VERSION 5.7 ;
  NOWIREEXTENSIONATPIN ON ;
  DIVIDERCHAR "/" ;
  BUSBITCHARS "[]" ;
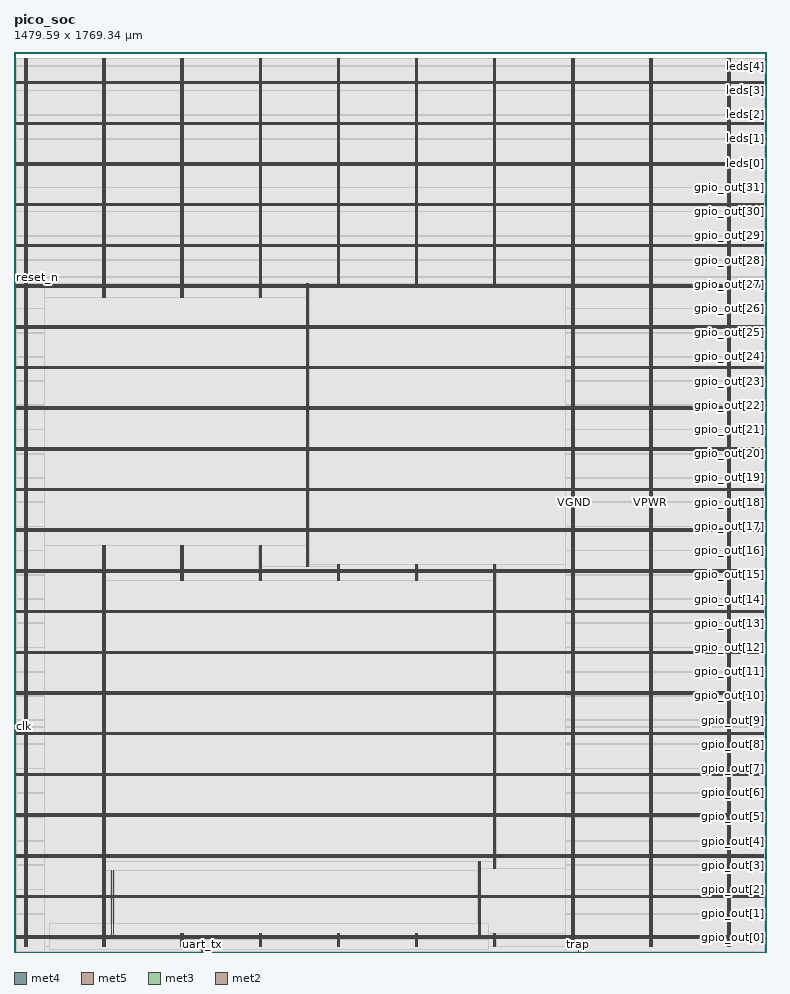
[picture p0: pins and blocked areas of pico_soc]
MACRO pico_soc
  CLASS BLOCK ;
  FOREIGN pico_soc ;
  ORIGIN 0.000 0.000 ;
  SIZE 1479.590 BY 1769.335 ;
  PIN VGND
    DIRECTION INOUT ;
    USE GROUND ;
    PORT
      LAYER met4 ;
        RECT 24.340 10.640 25.940 1757.360 ;
    END
    PORT
      LAYER met4 ;
        RECT 177.940 10.640 179.540 799.645 ;
    END
    PORT
      LAYER met4 ;
        RECT 177.940 1287.055 179.540 1757.360 ;
    END
    PORT
      LAYER met4 ;
        RECT 331.540 10.640 333.140 35.515 ;
    END
    PORT
      LAYER met4 ;
        RECT 331.540 730.325 333.140 799.645 ;
    END
    PORT
      LAYER met4 ;
        RECT 331.540 1287.055 333.140 1757.360 ;
    END
    PORT
      LAYER met4 ;
        RECT 485.140 10.640 486.740 35.515 ;
    END
    PORT
      LAYER met4 ;
        RECT 485.140 730.325 486.740 799.645 ;
    END
    PORT
      LAYER met4 ;
        RECT 485.140 1287.055 486.740 1757.360 ;
    END
    PORT
      LAYER met4 ;
        RECT 638.740 10.640 640.340 35.515 ;
    END
    PORT
      LAYER met4 ;
        RECT 638.740 730.325 640.340 762.080 ;
    END
    PORT
      LAYER met4 ;
        RECT 638.740 1310.030 640.340 1757.360 ;
    END
    PORT
      LAYER met4 ;
        RECT 792.340 10.640 793.940 35.515 ;
    END
    PORT
      LAYER met4 ;
        RECT 792.340 730.325 793.940 762.080 ;
    END
    PORT
      LAYER met4 ;
        RECT 792.340 1310.030 793.940 1757.360 ;
    END
    PORT
      LAYER met4 ;
        RECT 945.940 10.640 947.540 35.995 ;
    END
    PORT
      LAYER met4 ;
        RECT 945.940 163.685 947.540 762.080 ;
    END
    PORT
      LAYER met4 ;
        RECT 945.940 1310.030 947.540 1757.360 ;
    END
    PORT
      LAYER met4 ;
        RECT 1099.540 10.640 1101.140 1757.360 ;
    END
    PORT
      LAYER met4 ;
        RECT 1253.140 10.640 1254.740 1757.360 ;
    END
    PORT
      LAYER met4 ;
        RECT 1406.740 10.640 1408.340 1757.360 ;
    END
    PORT
      LAYER met5 ;
        RECT 5.280 30.030 1474.080 31.630 ;
    END
    PORT
      LAYER met5 ;
        RECT 5.280 110.030 1474.080 111.630 ;
    END
    PORT
      LAYER met5 ;
        RECT 5.280 190.030 1474.080 191.630 ;
    END
    PORT
      LAYER met5 ;
        RECT 5.280 270.030 1474.080 271.630 ;
    END
    PORT
      LAYER met5 ;
        RECT 5.280 350.030 1474.080 351.630 ;
    END
    PORT
      LAYER met5 ;
        RECT 5.280 430.030 1474.080 431.630 ;
    END
    PORT
      LAYER met5 ;
        RECT 5.280 510.030 1474.080 511.630 ;
    END
    PORT
      LAYER met5 ;
        RECT 5.280 590.030 1474.080 591.630 ;
    END
    PORT
      LAYER met5 ;
        RECT 5.280 670.030 1474.080 671.630 ;
    END
    PORT
      LAYER met5 ;
        RECT 5.280 750.030 1474.080 751.630 ;
    END
    PORT
      LAYER met5 ;
        RECT 5.280 830.030 1474.080 831.630 ;
    END
    PORT
      LAYER met5 ;
        RECT 5.280 910.030 1474.080 911.630 ;
    END
    PORT
      LAYER met5 ;
        RECT 5.280 990.030 1474.080 991.630 ;
    END
    PORT
      LAYER met5 ;
        RECT 5.280 1070.030 1474.080 1071.630 ;
    END
    PORT
      LAYER met5 ;
        RECT 5.280 1150.030 1474.080 1151.630 ;
    END
    PORT
      LAYER met5 ;
        RECT 5.280 1230.030 1474.080 1231.630 ;
    END
    PORT
      LAYER met5 ;
        RECT 5.280 1310.030 1474.080 1311.630 ;
    END
    PORT
      LAYER met5 ;
        RECT 5.280 1390.030 1474.080 1391.630 ;
    END
    PORT
      LAYER met5 ;
        RECT 5.280 1470.030 1474.080 1471.630 ;
    END
    PORT
      LAYER met5 ;
        RECT 5.280 1550.030 1474.080 1551.630 ;
    END
    PORT
      LAYER met5 ;
        RECT 5.280 1630.030 1474.080 1631.630 ;
    END
    PORT
      LAYER met5 ;
        RECT 5.280 1710.030 1474.080 1711.630 ;
    END
    PORT
      LAYER met4 ;
        RECT 194.700 26.960 196.300 160.720 ;
    END
    PORT
      LAYER met4 ;
        RECT 578.340 758.640 579.940 1314.000 ;
    END
    PORT
      LAYER met4 ;
        RECT 915.980 26.960 917.580 177.040 ;
    END
  END VGND
  PIN VPWR
    DIRECTION INOUT ;
    USE POWER ;
    PORT
      LAYER met4 ;
        RECT 21.040 10.640 22.640 1757.360 ;
    END
    PORT
      LAYER met4 ;
        RECT 174.640 10.640 176.240 799.645 ;
    END
    PORT
      LAYER met4 ;
        RECT 174.640 1287.055 176.240 1757.360 ;
    END
    PORT
      LAYER met4 ;
        RECT 328.240 10.640 329.840 35.515 ;
    END
    PORT
      LAYER met4 ;
        RECT 328.240 730.325 329.840 799.645 ;
    END
    PORT
      LAYER met4 ;
        RECT 328.240 1287.055 329.840 1757.360 ;
    END
    PORT
      LAYER met4 ;
        RECT 481.840 10.640 483.440 35.515 ;
    END
    PORT
      LAYER met4 ;
        RECT 481.840 730.325 483.440 799.645 ;
    END
    PORT
      LAYER met4 ;
        RECT 481.840 1287.055 483.440 1757.360 ;
    END
    PORT
      LAYER met4 ;
        RECT 635.440 10.640 637.040 35.515 ;
    END
    PORT
      LAYER met4 ;
        RECT 635.440 730.325 637.040 762.080 ;
    END
    PORT
      LAYER met4 ;
        RECT 635.440 1310.295 637.040 1757.360 ;
    END
    PORT
      LAYER met4 ;
        RECT 789.040 10.640 790.640 35.515 ;
    END
    PORT
      LAYER met4 ;
        RECT 789.040 730.325 790.640 761.160 ;
    END
    PORT
      LAYER met4 ;
        RECT 789.040 1310.295 790.640 1757.360 ;
    END
    PORT
      LAYER met4 ;
        RECT 942.640 10.640 944.240 35.995 ;
    END
    PORT
      LAYER met4 ;
        RECT 942.640 163.685 944.240 762.080 ;
    END
    PORT
      LAYER met4 ;
        RECT 942.640 1310.295 944.240 1757.360 ;
    END
    PORT
      LAYER met4 ;
        RECT 1096.240 10.640 1097.840 1757.360 ;
    END
    PORT
      LAYER met4 ;
        RECT 1249.840 10.640 1251.440 1757.360 ;
    END
    PORT
      LAYER met4 ;
        RECT 1403.440 10.640 1405.040 1757.360 ;
    END
    PORT
      LAYER met5 ;
        RECT 5.280 26.730 1474.080 28.330 ;
    END
    PORT
      LAYER met5 ;
        RECT 5.280 106.730 1474.080 108.330 ;
    END
    PORT
      LAYER met5 ;
        RECT 5.280 186.730 1474.080 188.330 ;
    END
    PORT
      LAYER met5 ;
        RECT 5.280 266.730 1474.080 268.330 ;
    END
    PORT
      LAYER met5 ;
        RECT 5.280 346.730 1474.080 348.330 ;
    END
    PORT
      LAYER met5 ;
        RECT 5.280 426.730 1474.080 428.330 ;
    END
    PORT
      LAYER met5 ;
        RECT 5.280 506.730 1474.080 508.330 ;
    END
    PORT
      LAYER met5 ;
        RECT 5.280 586.730 1474.080 588.330 ;
    END
    PORT
      LAYER met5 ;
        RECT 5.280 666.730 1474.080 668.330 ;
    END
    PORT
      LAYER met5 ;
        RECT 5.280 746.730 1474.080 748.330 ;
    END
    PORT
      LAYER met5 ;
        RECT 5.280 826.730 1474.080 828.330 ;
    END
    PORT
      LAYER met5 ;
        RECT 5.280 906.730 1474.080 908.330 ;
    END
    PORT
      LAYER met5 ;
        RECT 5.280 986.730 1474.080 988.330 ;
    END
    PORT
      LAYER met5 ;
        RECT 5.280 1066.730 1474.080 1068.330 ;
    END
    PORT
      LAYER met5 ;
        RECT 5.280 1146.730 1474.080 1148.330 ;
    END
    PORT
      LAYER met5 ;
        RECT 5.280 1226.730 1474.080 1228.330 ;
    END
    PORT
      LAYER met5 ;
        RECT 5.280 1306.730 1474.080 1308.330 ;
    END
    PORT
      LAYER met5 ;
        RECT 5.280 1386.730 1474.080 1388.330 ;
    END
    PORT
      LAYER met5 ;
        RECT 5.280 1466.730 1474.080 1468.330 ;
    END
    PORT
      LAYER met5 ;
        RECT 5.280 1546.730 1474.080 1548.330 ;
    END
    PORT
      LAYER met5 ;
        RECT 5.280 1626.730 1474.080 1628.330 ;
    END
    PORT
      LAYER met5 ;
        RECT 5.280 1706.730 1474.080 1708.330 ;
    END
    PORT
      LAYER met4 ;
        RECT 191.020 26.960 192.620 160.720 ;
    END
    PORT
      LAYER met4 ;
        RECT 574.660 758.640 576.260 1314.000 ;
    END
    PORT
      LAYER met4 ;
        RECT 912.300 26.960 913.900 177.040 ;
    END
  END VPWR
  PIN clk
    DIRECTION INPUT ;
    USE SIGNAL ;
    ANTENNAGATEAREA 2.573400 ;
    ANTENNADIFFAREA 0.869400 ;
    PORT
      LAYER met3 ;
        RECT 0.000 442.040 17.320 442.640 ;
    END
  END clk
  PIN gpio_out[0]
    DIRECTION OUTPUT ;
    USE SIGNAL ;
    ANTENNAGATEAREA 0.434700 ;
    ANTENNADIFFAREA 1.229900 ;
    PORT
      LAYER met3 ;
        RECT 1475.590 27.240 1479.590 27.840 ;
    END
  END gpio_out[0]
  PIN gpio_out[10]
    DIRECTION OUTPUT ;
    USE SIGNAL ;
    ANTENNAGATEAREA 0.434700 ;
    ANTENNADIFFAREA 1.229900 ;
    PORT
      LAYER met3 ;
        RECT 1475.590 503.240 1479.590 503.840 ;
    END
  END gpio_out[10]
  PIN gpio_out[11]
    DIRECTION OUTPUT ;
    USE SIGNAL ;
    ANTENNAGATEAREA 0.434700 ;
    ANTENNADIFFAREA 1.229900 ;
    PORT
      LAYER met3 ;
        RECT 1475.590 550.840 1479.590 551.440 ;
    END
  END gpio_out[11]
  PIN gpio_out[12]
    DIRECTION OUTPUT ;
    USE SIGNAL ;
    ANTENNAGATEAREA 0.434700 ;
    ANTENNADIFFAREA 1.229900 ;
    PORT
      LAYER met3 ;
        RECT 1475.590 598.440 1479.590 599.040 ;
    END
  END gpio_out[12]
  PIN gpio_out[13]
    DIRECTION OUTPUT ;
    USE SIGNAL ;
    ANTENNAGATEAREA 0.434700 ;
    ANTENNADIFFAREA 1.229900 ;
    PORT
      LAYER met3 ;
        RECT 1475.590 646.040 1479.590 646.640 ;
    END
  END gpio_out[13]
  PIN gpio_out[14]
    DIRECTION OUTPUT ;
    USE SIGNAL ;
    ANTENNAGATEAREA 0.434700 ;
    ANTENNADIFFAREA 1.229900 ;
    PORT
      LAYER met3 ;
        RECT 1475.590 693.640 1479.590 694.240 ;
    END
  END gpio_out[14]
  PIN gpio_out[15]
    DIRECTION OUTPUT ;
    USE SIGNAL ;
    ANTENNAGATEAREA 0.434700 ;
    ANTENNADIFFAREA 1.229900 ;
    PORT
      LAYER met3 ;
        RECT 1475.590 741.240 1479.590 741.840 ;
    END
  END gpio_out[15]
  PIN gpio_out[16]
    DIRECTION OUTPUT ;
    USE SIGNAL ;
    ANTENNAGATEAREA 0.434700 ;
    ANTENNADIFFAREA 1.229900 ;
    PORT
      LAYER met3 ;
        RECT 1475.590 788.840 1479.590 789.440 ;
    END
  END gpio_out[16]
  PIN gpio_out[17]
    DIRECTION OUTPUT ;
    USE SIGNAL ;
    ANTENNAGATEAREA 0.434700 ;
    ANTENNADIFFAREA 1.229900 ;
    PORT
      LAYER met3 ;
        RECT 1475.590 836.440 1479.590 837.040 ;
    END
  END gpio_out[17]
  PIN gpio_out[18]
    DIRECTION OUTPUT ;
    USE SIGNAL ;
    ANTENNAGATEAREA 0.434700 ;
    ANTENNADIFFAREA 1.229900 ;
    PORT
      LAYER met3 ;
        RECT 1475.590 884.040 1479.590 884.640 ;
    END
  END gpio_out[18]
  PIN gpio_out[19]
    DIRECTION OUTPUT ;
    USE SIGNAL ;
    ANTENNAGATEAREA 0.434700 ;
    ANTENNADIFFAREA 1.229900 ;
    PORT
      LAYER met3 ;
        RECT 1475.590 931.640 1479.590 932.240 ;
    END
  END gpio_out[19]
  PIN gpio_out[1]
    DIRECTION OUTPUT ;
    USE SIGNAL ;
    ANTENNAGATEAREA 0.434700 ;
    ANTENNADIFFAREA 1.229900 ;
    PORT
      LAYER met3 ;
        RECT 1475.590 74.840 1479.590 75.440 ;
    END
  END gpio_out[1]
  PIN gpio_out[20]
    DIRECTION OUTPUT ;
    USE SIGNAL ;
    ANTENNAGATEAREA 0.434700 ;
    ANTENNADIFFAREA 1.229900 ;
    PORT
      LAYER met3 ;
        RECT 1475.590 979.240 1479.590 979.840 ;
    END
  END gpio_out[20]
  PIN gpio_out[21]
    DIRECTION OUTPUT ;
    USE SIGNAL ;
    ANTENNAGATEAREA 0.434700 ;
    ANTENNADIFFAREA 1.229900 ;
    PORT
      LAYER met3 ;
        RECT 1475.590 1026.840 1479.590 1027.440 ;
    END
  END gpio_out[21]
  PIN gpio_out[22]
    DIRECTION OUTPUT ;
    USE SIGNAL ;
    ANTENNAGATEAREA 0.434700 ;
    ANTENNADIFFAREA 1.229900 ;
    PORT
      LAYER met3 ;
        RECT 1475.590 1074.440 1479.590 1075.040 ;
    END
  END gpio_out[22]
  PIN gpio_out[23]
    DIRECTION OUTPUT ;
    USE SIGNAL ;
    ANTENNAGATEAREA 0.434700 ;
    ANTENNADIFFAREA 1.229900 ;
    PORT
      LAYER met3 ;
        RECT 1475.590 1122.040 1479.590 1122.640 ;
    END
  END gpio_out[23]
  PIN gpio_out[24]
    DIRECTION OUTPUT ;
    USE SIGNAL ;
    ANTENNAGATEAREA 0.434700 ;
    ANTENNADIFFAREA 1.229900 ;
    PORT
      LAYER met3 ;
        RECT 1475.590 1169.640 1479.590 1170.240 ;
    END
  END gpio_out[24]
  PIN gpio_out[25]
    DIRECTION OUTPUT ;
    USE SIGNAL ;
    ANTENNAGATEAREA 0.434700 ;
    ANTENNADIFFAREA 1.229900 ;
    PORT
      LAYER met3 ;
        RECT 1475.590 1217.240 1479.590 1217.840 ;
    END
  END gpio_out[25]
  PIN gpio_out[26]
    DIRECTION OUTPUT ;
    USE SIGNAL ;
    ANTENNAGATEAREA 0.434700 ;
    ANTENNADIFFAREA 1.229900 ;
    PORT
      LAYER met3 ;
        RECT 1475.590 1264.840 1479.590 1265.440 ;
    END
  END gpio_out[26]
  PIN gpio_out[27]
    DIRECTION OUTPUT ;
    USE SIGNAL ;
    ANTENNAGATEAREA 0.434700 ;
    ANTENNADIFFAREA 1.229900 ;
    PORT
      LAYER met3 ;
        RECT 1475.590 1312.440 1479.590 1313.040 ;
    END
  END gpio_out[27]
  PIN gpio_out[28]
    DIRECTION OUTPUT ;
    USE SIGNAL ;
    ANTENNAGATEAREA 0.434700 ;
    ANTENNADIFFAREA 1.229900 ;
    PORT
      LAYER met3 ;
        RECT 1475.590 1360.040 1479.590 1360.640 ;
    END
  END gpio_out[28]
  PIN gpio_out[29]
    DIRECTION OUTPUT ;
    USE SIGNAL ;
    ANTENNAGATEAREA 0.434700 ;
    ANTENNADIFFAREA 1.229900 ;
    PORT
      LAYER met3 ;
        RECT 1475.590 1407.640 1479.590 1408.240 ;
    END
  END gpio_out[29]
  PIN gpio_out[2]
    DIRECTION OUTPUT ;
    USE SIGNAL ;
    ANTENNAGATEAREA 0.434700 ;
    ANTENNADIFFAREA 1.229900 ;
    PORT
      LAYER met3 ;
        RECT 1475.590 122.440 1479.590 123.040 ;
    END
  END gpio_out[2]
  PIN gpio_out[30]
    DIRECTION OUTPUT ;
    USE SIGNAL ;
    ANTENNAGATEAREA 0.434700 ;
    ANTENNADIFFAREA 1.229900 ;
    PORT
      LAYER met3 ;
        RECT 1475.590 1455.240 1479.590 1455.840 ;
    END
  END gpio_out[30]
  PIN gpio_out[31]
    DIRECTION OUTPUT ;
    USE SIGNAL ;
    ANTENNAGATEAREA 0.434700 ;
    ANTENNADIFFAREA 1.229900 ;
    PORT
      LAYER met3 ;
        RECT 1475.590 1502.840 1479.590 1503.440 ;
    END
  END gpio_out[31]
  PIN gpio_out[3]
    DIRECTION OUTPUT ;
    USE SIGNAL ;
    ANTENNAGATEAREA 0.434700 ;
    ANTENNADIFFAREA 1.229900 ;
    PORT
      LAYER met3 ;
        RECT 1475.590 170.040 1479.590 170.640 ;
    END
  END gpio_out[3]
  PIN gpio_out[4]
    DIRECTION OUTPUT ;
    USE SIGNAL ;
    ANTENNAGATEAREA 0.434700 ;
    ANTENNADIFFAREA 1.229900 ;
    PORT
      LAYER met3 ;
        RECT 1475.590 217.640 1479.590 218.240 ;
    END
  END gpio_out[4]
  PIN gpio_out[5]
    DIRECTION OUTPUT ;
    USE SIGNAL ;
    ANTENNAGATEAREA 0.434700 ;
    ANTENNADIFFAREA 1.229900 ;
    PORT
      LAYER met3 ;
        RECT 1475.590 265.240 1479.590 265.840 ;
    END
  END gpio_out[5]
  PIN gpio_out[6]
    DIRECTION OUTPUT ;
    USE SIGNAL ;
    ANTENNAGATEAREA 0.434700 ;
    ANTENNADIFFAREA 1.229900 ;
    PORT
      LAYER met3 ;
        RECT 1475.590 312.840 1479.590 313.440 ;
    END
  END gpio_out[6]
  PIN gpio_out[7]
    DIRECTION OUTPUT ;
    USE SIGNAL ;
    ANTENNAGATEAREA 0.434700 ;
    ANTENNADIFFAREA 1.229900 ;
    PORT
      LAYER met3 ;
        RECT 1475.590 360.440 1479.590 361.040 ;
    END
  END gpio_out[7]
  PIN gpio_out[8]
    DIRECTION OUTPUT ;
    USE SIGNAL ;
    ANTENNAGATEAREA 0.434700 ;
    ANTENNADIFFAREA 1.229900 ;
    PORT
      LAYER met3 ;
        RECT 1475.590 408.040 1479.590 408.640 ;
    END
  END gpio_out[8]
  PIN gpio_out[9]
    DIRECTION OUTPUT ;
    USE SIGNAL ;
    ANTENNAGATEAREA 0.434700 ;
    ANTENNADIFFAREA 1.229900 ;
    PORT
      LAYER met3 ;
        RECT 1475.590 455.640 1479.590 456.240 ;
    END
  END gpio_out[9]
  PIN leds[0]
    DIRECTION OUTPUT ;
    USE SIGNAL ;
    ANTENNAGATEAREA 0.434700 ;
    ANTENNADIFFAREA 1.229900 ;
    PORT
      LAYER met3 ;
        RECT 1475.590 1550.440 1479.590 1551.040 ;
    END
  END leds[0]
  PIN leds[1]
    DIRECTION OUTPUT ;
    USE SIGNAL ;
    ANTENNAGATEAREA 0.434700 ;
    ANTENNADIFFAREA 1.229900 ;
    PORT
      LAYER met3 ;
        RECT 1475.590 1598.040 1479.590 1598.640 ;
    END
  END leds[1]
  PIN leds[2]
    DIRECTION OUTPUT ;
    USE SIGNAL ;
    ANTENNAGATEAREA 0.434700 ;
    ANTENNADIFFAREA 1.229900 ;
    PORT
      LAYER met3 ;
        RECT 1475.590 1645.640 1479.590 1646.240 ;
    END
  END leds[2]
  PIN leds[3]
    DIRECTION OUTPUT ;
    USE SIGNAL ;
    ANTENNAGATEAREA 0.434700 ;
    ANTENNADIFFAREA 1.229900 ;
    PORT
      LAYER met3 ;
        RECT 1475.590 1693.240 1479.590 1693.840 ;
    END
  END leds[3]
  PIN leds[4]
    DIRECTION OUTPUT ;
    USE SIGNAL ;
    ANTENNAGATEAREA 0.434700 ;
    ANTENNADIFFAREA 1.229900 ;
    PORT
      LAYER met3 ;
        RECT 1475.590 1740.840 1479.590 1741.440 ;
    END
  END leds[4]
  PIN reset_n
    DIRECTION INPUT ;
    USE SIGNAL ;
    ANTENNAGATEAREA 0.647700 ;
    ANTENNADIFFAREA 0.434700 ;
    PORT
      LAYER met3 ;
        RECT 0.000 1326.040 4.000 1326.640 ;
    END
  END reset_n
  PIN trap
    DIRECTION OUTPUT ;
    USE SIGNAL ;
    ANTENNAGATEAREA 0.434700 ;
    ANTENNADIFFAREA 1.229900 ;
    PORT
      LAYER met2 ;
        RECT 1109.150 0.000 1109.430 4.000 ;
    END
  END trap
  PIN uart_tx
    DIRECTION OUTPUT ;
    USE SIGNAL ;
    ANTENNAGATEAREA 0.434700 ;
    ANTENNADIFFAREA 1.229900 ;
    PORT
      LAYER met2 ;
        RECT 369.470 0.000 369.750 4.000 ;
    END
  END uart_tx
  OBS
      LAYER nwell ;
        RECT 5.330 10.795 1474.030 1757.205 ;
      LAYER li1 ;
        RECT 5.520 10.795 1473.840 1757.205 ;
      LAYER met1 ;
        RECT 5.520 0.040 1473.840 1757.360 ;
      LAYER met2 ;
        RECT 6.990 4.280 1472.370 1757.305 ;
        RECT 6.990 0.010 369.190 4.280 ;
        RECT 370.030 0.010 1108.870 4.280 ;
        RECT 1109.710 0.010 1472.370 4.280 ;
      LAYER met3 ;
        RECT 4.000 1741.840 1475.590 1757.285 ;
        RECT 4.000 1740.440 1475.190 1741.840 ;
        RECT 4.000 1694.240 1475.590 1740.440 ;
        RECT 4.000 1692.840 1475.190 1694.240 ;
        RECT 4.000 1646.640 1475.590 1692.840 ;
        RECT 4.000 1645.240 1475.190 1646.640 ;
        RECT 4.000 1599.040 1475.590 1645.240 ;
        RECT 4.000 1597.640 1475.190 1599.040 ;
        RECT 4.000 1551.440 1475.590 1597.640 ;
        RECT 4.000 1550.040 1475.190 1551.440 ;
        RECT 4.000 1503.840 1475.590 1550.040 ;
        RECT 4.000 1502.440 1475.190 1503.840 ;
        RECT 4.000 1456.240 1475.590 1502.440 ;
        RECT 4.000 1454.840 1475.190 1456.240 ;
        RECT 4.000 1408.640 1475.590 1454.840 ;
        RECT 4.000 1407.240 1475.190 1408.640 ;
        RECT 4.000 1361.040 1475.590 1407.240 ;
        RECT 4.000 1359.640 1475.190 1361.040 ;
        RECT 4.000 1327.040 1475.590 1359.640 ;
        RECT 4.400 1325.640 1475.590 1327.040 ;
        RECT 4.000 1313.440 1475.590 1325.640 ;
        RECT 4.000 1312.040 1475.190 1313.440 ;
        RECT 4.000 1265.840 1475.590 1312.040 ;
        RECT 4.000 1264.440 1475.190 1265.840 ;
        RECT 4.000 1218.240 1475.590 1264.440 ;
        RECT 4.000 1216.840 1475.190 1218.240 ;
        RECT 4.000 1170.640 1475.590 1216.840 ;
        RECT 4.000 1169.240 1475.190 1170.640 ;
        RECT 4.000 1123.040 1475.590 1169.240 ;
        RECT 4.000 1121.640 1475.190 1123.040 ;
        RECT 4.000 1075.440 1475.590 1121.640 ;
        RECT 4.000 1074.040 1475.190 1075.440 ;
        RECT 4.000 1027.840 1475.590 1074.040 ;
        RECT 4.000 1026.440 1475.190 1027.840 ;
        RECT 4.000 980.240 1475.590 1026.440 ;
        RECT 4.000 978.840 1475.190 980.240 ;
        RECT 4.000 932.640 1475.590 978.840 ;
        RECT 4.000 931.240 1475.190 932.640 ;
        RECT 4.000 885.040 1475.590 931.240 ;
        RECT 4.000 883.640 1475.190 885.040 ;
        RECT 4.000 837.440 1475.590 883.640 ;
        RECT 4.000 836.040 1475.190 837.440 ;
        RECT 4.000 789.840 1475.590 836.040 ;
        RECT 4.000 788.440 1475.190 789.840 ;
        RECT 4.000 742.240 1475.590 788.440 ;
        RECT 4.000 740.840 1475.190 742.240 ;
        RECT 4.000 694.640 1475.590 740.840 ;
        RECT 4.000 693.240 1475.190 694.640 ;
        RECT 4.000 647.040 1475.590 693.240 ;
        RECT 4.000 645.640 1475.190 647.040 ;
        RECT 4.000 599.440 1475.590 645.640 ;
        RECT 4.000 598.040 1475.190 599.440 ;
        RECT 4.000 551.840 1475.590 598.040 ;
        RECT 4.000 550.440 1475.190 551.840 ;
        RECT 4.000 504.240 1475.590 550.440 ;
        RECT 4.000 502.840 1475.190 504.240 ;
        RECT 4.000 456.640 1475.590 502.840 ;
        RECT 4.000 455.240 1475.190 456.640 ;
        RECT 4.000 443.040 1475.590 455.240 ;
        RECT 17.720 441.640 1475.590 443.040 ;
        RECT 4.000 409.040 1475.590 441.640 ;
        RECT 4.000 407.640 1475.190 409.040 ;
        RECT 4.000 361.440 1475.590 407.640 ;
        RECT 4.000 360.040 1475.190 361.440 ;
        RECT 4.000 313.840 1475.590 360.040 ;
        RECT 4.000 312.440 1475.190 313.840 ;
        RECT 4.000 266.240 1475.590 312.440 ;
        RECT 4.000 264.840 1475.190 266.240 ;
        RECT 4.000 218.640 1475.590 264.840 ;
        RECT 4.000 217.240 1475.190 218.640 ;
        RECT 4.000 171.040 1475.590 217.240 ;
        RECT 4.000 169.640 1475.190 171.040 ;
        RECT 4.000 123.440 1475.590 169.640 ;
        RECT 4.000 122.040 1475.190 123.440 ;
        RECT 4.000 75.840 1475.590 122.040 ;
        RECT 4.000 74.440 1475.190 75.840 ;
        RECT 4.000 28.240 1475.590 74.440 ;
        RECT 4.000 26.840 1475.190 28.240 ;
        RECT 4.000 0.175 1475.590 26.840 ;
      LAYER met4 ;
        RECT 60.095 1286.655 174.240 1312.225 ;
        RECT 176.640 1286.655 177.540 1312.225 ;
        RECT 179.940 1286.655 327.840 1312.225 ;
        RECT 330.240 1286.655 331.140 1312.225 ;
        RECT 333.540 1286.655 481.440 1312.225 ;
        RECT 483.840 1286.655 484.740 1312.225 ;
        RECT 487.140 1286.655 574.260 1312.225 ;
        RECT 60.095 800.045 574.260 1286.655 ;
        RECT 60.095 10.240 174.240 800.045 ;
        RECT 176.640 10.240 177.540 800.045 ;
        RECT 179.940 729.925 327.840 800.045 ;
        RECT 330.240 729.925 331.140 800.045 ;
        RECT 333.540 729.925 481.440 800.045 ;
        RECT 483.840 729.925 484.740 800.045 ;
        RECT 487.140 758.240 574.260 800.045 ;
        RECT 576.660 758.240 577.940 1312.225 ;
        RECT 580.340 1309.895 635.040 1312.225 ;
        RECT 637.440 1309.895 638.340 1312.225 ;
        RECT 580.340 1309.630 638.340 1309.895 ;
        RECT 640.740 1309.895 788.640 1312.225 ;
        RECT 791.040 1309.895 791.940 1312.225 ;
        RECT 640.740 1309.630 791.940 1309.895 ;
        RECT 794.340 1309.895 942.240 1312.225 ;
        RECT 944.640 1309.895 945.540 1312.225 ;
        RECT 794.340 1309.630 945.540 1309.895 ;
        RECT 947.940 1309.630 1083.375 1312.225 ;
        RECT 580.340 762.480 1083.375 1309.630 ;
        RECT 580.340 758.240 635.040 762.480 ;
        RECT 487.140 729.925 635.040 758.240 ;
        RECT 637.440 729.925 638.340 762.480 ;
        RECT 640.740 761.560 791.940 762.480 ;
        RECT 640.740 729.925 788.640 761.560 ;
        RECT 791.040 729.925 791.940 761.560 ;
        RECT 794.340 729.925 942.240 762.480 ;
        RECT 179.940 177.440 942.240 729.925 ;
        RECT 179.940 161.120 911.900 177.440 ;
        RECT 179.940 26.560 190.620 161.120 ;
        RECT 193.020 26.560 194.300 161.120 ;
        RECT 196.700 35.915 911.900 161.120 ;
        RECT 196.700 26.560 327.840 35.915 ;
        RECT 179.940 10.240 327.840 26.560 ;
        RECT 330.240 10.240 331.140 35.915 ;
        RECT 333.540 10.240 481.440 35.915 ;
        RECT 483.840 10.240 484.740 35.915 ;
        RECT 487.140 10.240 635.040 35.915 ;
        RECT 637.440 10.240 638.340 35.915 ;
        RECT 640.740 10.240 788.640 35.915 ;
        RECT 791.040 10.240 791.940 35.915 ;
        RECT 794.340 26.560 911.900 35.915 ;
        RECT 914.300 26.560 915.580 177.440 ;
        RECT 917.980 163.285 942.240 177.440 ;
        RECT 944.640 163.285 945.540 762.480 ;
        RECT 947.940 163.285 1083.375 762.480 ;
        RECT 917.980 36.395 1083.375 163.285 ;
        RECT 917.980 26.560 942.240 36.395 ;
        RECT 794.340 10.240 942.240 26.560 ;
        RECT 944.640 10.240 945.540 36.395 ;
        RECT 947.940 10.240 1083.375 36.395 ;
        RECT 60.095 0.175 1083.375 10.240 ;
      LAYER met5 ;
        RECT 69.580 33.230 932.300 56.900 ;
        RECT 69.580 4.300 932.300 25.130 ;
  END
END pico_soc
END LIBRARY

